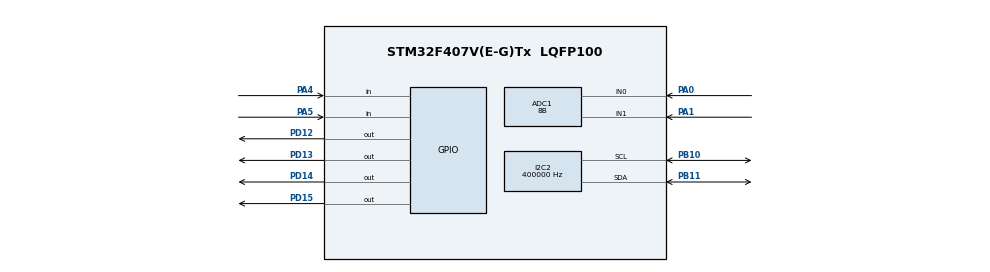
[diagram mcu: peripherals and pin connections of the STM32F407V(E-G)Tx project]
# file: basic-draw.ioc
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ADC1.Channel-2\#ChannelRegularConversion=ADC_CHANNEL_0
ADC1.Channel-3\#ChannelRegularConversion=ADC_CHANNEL_1
ADC1.ClockPrescaler=ADC_CLOCK_SYNC_PCLK_DIV4
ADC1.ContinuousConvMode=ENABLE
ADC1.DMAContinuousRequests=ENABLE
ADC1.EOCSelection=ADC_EOC_SEQ_CONV
ADC1.NbrOfConversion=2
ADC1.NbrOfConversionFlag=1
ADC1.Rank-2\#ChannelRegularConversion=1
ADC1.Rank-3\#ChannelRegularConversion=2
ADC1.Resolution=ADC_RESOLUTION_8B
ADC1.SamplingTime-2\#ChannelRegularConversion=ADC_SAMPLETIME_480CYCLES
ADC1.SamplingTime-3\#ChannelRegularConversion=ADC_SAMPLETIME_480CYCLES
ADC1.ScanConvMode=ENABLE
ADC1.master=1
Dma.ADC1.0.Direction=DMA_PERIPH_TO_MEMORY
Dma.ADC1.0.FIFOMode=DMA_FIFOMODE_DISABLE
Dma.ADC1.0.Instance=DMA2_Stream0
Dma.ADC1.0.MemDataAlignment=DMA_MDATAALIGN_BYTE
Dma.ADC1.0.MemInc=DMA_MINC_ENABLE
Dma.ADC1.0.Mode=DMA_CIRCULAR
Dma.ADC1.0.PeriphDataAlignment=DMA_PDATAALIGN_BYTE
Dma.ADC1.0.PeriphInc=DMA_PINC_DISABLE
Dma.ADC1.0.Priority=DMA_PRIORITY_LOW
Dma.Request0=ADC1
I2C2.ClockSpeed=400000
I2C2.DutyCycle=I2C_DUTYCYCLE_16_9
I2C2.I2C_Mode=I2C_Fast
Mcu.Family=STM32F4
Mcu.Name=STM32F407V(E-G)Tx
Mcu.Package=LQFP100
NVIC.DMA2_Stream0_IRQn=true\:0\:0\:false\:false\:true\:false\:true
NVIC.PriorityGroup=NVIC_PRIORITYGROUP_4
NVIC.TIM2_IRQn=true\:0\:0\:false\:false\:true\:true\:true
PA0-WKUP.Signal=SharedAnalog_PA0
PA1.Signal=SharedAnalog_PA1
PA4.GPIO_PuPd=GPIO_PULLDOWN
PA4.Signal=GPIO_Input
PA5.GPIO_PuPd=GPIO_PULLDOWN
PA5.Signal=GPIO_Input
PB10.Mode=I2C
PB10.Signal=I2C2_SCL
PB11.Mode=I2C
PB11.Signal=I2C2_SDA
PD12.Signal=GPIO_Output
PD13.GPIO_Speed=GPIO_SPEED_FREQ_VERY_HIGH
PD13.Signal=GPIO_Output
PD14.Signal=GPIO_Output
PD15.Signal=GPIO_Output
ProjectManager.HeapSize=0x200
ProjectManager.StackSize=0x400
ProjectManager.TargetToolchain=STM32CubeIDE
RCC.48MHZClocksFreq_Value=84000000
RCC.AHBFreq_Value=168000000
RCC.APB1CLKDivider=RCC_HCLK_DIV16
RCC.APB1Freq_Value=10500000
RCC.APB1TimFreq_Value=21000000
RCC.APB2Freq_Value=168000000
RCC.APB2TimFreq_Value=168000000
RCC.CortexFreq_Value=168000000
RCC.HCLKFreq_Value=168000000
RCC.HSE_VALUE=25000000
RCC.HSI_VALUE=16000000
RCC.LSE_VALUE=32768
RCC.PLLM=8
RCC.PLLN=168
RCC.SYSCLKFreq_VALUE=168000000
RCC.SYSCLKSource=RCC_SYSCLKSOURCE_PLLCLK
RCC.VCOOutputFreq_Value=336000000
SH.SharedAnalog_PA0.0=GPIO_Analog
SH.SharedAnalog_PA0.1=ADC2_IN0
SH.SharedAnalog_PA0.2=ADC1_IN0,IN0
SH.SharedAnalog_PA1.0=GPIO_Analog
SH.SharedAnalog_PA1.1=ADC1_IN1,IN1
TIM2.CounterMode=TIM_COUNTERMODE_UP
TIM2.Period=50
TIM2.Prescaler=21000-1
TIM2.TIM_MasterOutputTrigger=TIM_TRGO_UPDATE
VP_TIM2_VS_ClockSourceINT.Mode=Internal
board=custom

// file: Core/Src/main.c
/* USER CODE BEGIN Header */
/**
  ******************************************************************************
  * @file           : main.c
  * @brief          : Main program body
  ******************************************************************************
  * @attention
  *
  * Copyright (c) 2022 STMicroelectronics.
  * All rights reserved.
  *
  * This software is licensed under terms that can be found in the LICENSE file
  * in the root directory of this software component.
  * If no LICENSE file comes with this software, it is provided AS-IS.
  *
  ******************************************************************************
  */
/* USER CODE END Header */
#include "main.h"

/* USER CODE BEGIN Includes */
#include <stdio.h>
#include "user_main.h"
/* USER CODE END Includes */

ADC_HandleTypeDef hadc1;
DMA_HandleTypeDef hdma_adc1;

I2C_HandleTypeDef hi2c2;

TIM_HandleTypeDef htim2;

void SystemClock_Config(void);
static void MX_TIM2_Init(void);
static void MX_GPIO_Init(void);
static void MX_I2C2_Init(void);
static void MX_DMA_Init(void);
static void MX_ADC1_Init(void);

int main(void)
{

  /* MCU Configuration--------------------------------------------------------*/

  /* Reset of all peripherals, Initializes the Flash interface and the Systick. */
  HAL_Init();

  /* Configure the system clock */
  SystemClock_Config();

  /* Initialize all configured peripherals */
  MX_TIM2_Init();
  MX_GPIO_Init();
  MX_I2C2_Init();
  MX_DMA_Init();
  MX_ADC1_Init();
  /* USER CODE BEGIN 2 */
  user_main();
  /* USER CODE END 2 */

  /* Infinite loop */
  while (1)
  {

  }
}

void SystemClock_Config(void)
{
  RCC_OscInitTypeDef RCC_OscInitStruct = {0};
  RCC_ClkInitTypeDef RCC_ClkInitStruct = {0};

  /** Configure the main internal regulator output voltage
  */
  __HAL_RCC_PWR_CLK_ENABLE();
  __HAL_PWR_VOLTAGESCALING_CONFIG(PWR_REGULATOR_VOLTAGE_SCALE1);
  /** Initializes the RCC Oscillators according to the specified parameters
  * in the RCC_OscInitTypeDef structure.
  */
  RCC_OscInitStruct.OscillatorType = RCC_OSCILLATORTYPE_HSI;
  RCC_OscInitStruct.HSIState = RCC_HSI_ON;
  RCC_OscInitStruct.HSICalibrationValue = RCC_HSICALIBRATION_DEFAULT;
  RCC_OscInitStruct.PLL.PLLState = RCC_PLL_ON;
  RCC_OscInitStruct.PLL.PLLSource = RCC_PLLSOURCE_HSI;
  RCC_OscInitStruct.PLL.PLLM = 8;
  RCC_OscInitStruct.PLL.PLLN = 168;
  RCC_OscInitStruct.PLL.PLLP = RCC_PLLP_DIV2;
  RCC_OscInitStruct.PLL.PLLQ = 4;
  if (HAL_RCC_OscConfig(&RCC_OscInitStruct) != HAL_OK)
  {
    Error_Handler();
  }
  /** Initializes the CPU, AHB and APB buses clocks
  */
  RCC_ClkInitStruct.ClockType = RCC_CLOCKTYPE_HCLK|RCC_CLOCKTYPE_SYSCLK
                              |RCC_CLOCKTYPE_PCLK1|RCC_CLOCKTYPE_PCLK2;
  RCC_ClkInitStruct.SYSCLKSource = RCC_SYSCLKSOURCE_PLLCLK;
  RCC_ClkInitStruct.AHBCLKDivider = RCC_SYSCLK_DIV1;
  RCC_ClkInitStruct.APB1CLKDivider = RCC_HCLK_DIV16;
  RCC_ClkInitStruct.APB2CLKDivider = RCC_HCLK_DIV2;

  if (HAL_RCC_ClockConfig(&RCC_ClkInitStruct, FLASH_LATENCY_5) != HAL_OK)
  {
    Error_Handler();
  }
}

static void MX_ADC1_Init(void)
{

  ADC_ChannelConfTypeDef sConfig = {0};

  /** Configure the global features of the ADC (Clock, Resolution, Data Alignment and number of conversion)
  */
  hadc1.Instance = ADC1;
  hadc1.Init.ClockPrescaler = ADC_CLOCK_SYNC_PCLK_DIV4;
  hadc1.Init.Resolution = ADC_RESOLUTION_8B;
  hadc1.Init.ScanConvMode = ENABLE;
  hadc1.Init.ContinuousConvMode = ENABLE;
  hadc1.Init.DiscontinuousConvMode = DISABLE;
  hadc1.Init.ExternalTrigConvEdge = ADC_EXTERNALTRIGCONVEDGE_NONE;
  hadc1.Init.ExternalTrigConv = ADC_SOFTWARE_START;
  hadc1.Init.DataAlign = ADC_DATAALIGN_RIGHT;
  hadc1.Init.NbrOfConversion = 2;
  hadc1.Init.DMAContinuousRequests = ENABLE;
  hadc1.Init.EOCSelection = ADC_EOC_SEQ_CONV;
  if (HAL_ADC_Init(&hadc1) != HAL_OK)
  {
    Error_Handler();
  }
  /** Configure for the selected ADC regular channel its corresponding rank in the sequencer and its sample time.
  */
  sConfig.Channel = ADC_CHANNEL_0;
  sConfig.Rank = 1;
  sConfig.SamplingTime = ADC_SAMPLETIME_480CYCLES;
  if (HAL_ADC_ConfigChannel(&hadc1, &sConfig) != HAL_OK)
  {
    Error_Handler();
  }
  /** Configure for the selected ADC regular channel its corresponding rank in the sequencer and its sample time.
  */
  sConfig.Channel = ADC_CHANNEL_1;
  sConfig.Rank = 2;
  if (HAL_ADC_ConfigChannel(&hadc1, &sConfig) != HAL_OK)
  {
    Error_Handler();
  }

}

static void MX_I2C2_Init(void)
{

  hi2c2.Instance = I2C2;
  hi2c2.Init.ClockSpeed = 400000;
  hi2c2.Init.DutyCycle = I2C_DUTYCYCLE_16_9;
  hi2c2.Init.OwnAddress1 = 0;
  hi2c2.Init.AddressingMode = I2C_ADDRESSINGMODE_7BIT;
  hi2c2.Init.DualAddressMode = I2C_DUALADDRESS_DISABLE;
  hi2c2.Init.OwnAddress2 = 0;
  hi2c2.Init.GeneralCallMode = I2C_GENERALCALL_DISABLE;
  hi2c2.Init.NoStretchMode = I2C_NOSTRETCH_DISABLE;
  if (HAL_I2C_Init(&hi2c2) != HAL_OK)
  {
    Error_Handler();
  }

}

static void MX_TIM2_Init(void)
{

  TIM_ClockConfigTypeDef sClockSourceConfig = {0};
  TIM_MasterConfigTypeDef sMasterConfig = {0};

  htim2.Instance = TIM2;
  htim2.Init.Prescaler = 21000-1;
  htim2.Init.CounterMode = TIM_COUNTERMODE_UP;
  htim2.Init.Period = 50;
  htim2.Init.ClockDivision = TIM_CLOCKDIVISION_DIV1;
  htim2.Init.AutoReloadPreload = TIM_AUTORELOAD_PRELOAD_DISABLE;
  if (HAL_TIM_Base_Init(&htim2) != HAL_OK)
  {
    Error_Handler();
  }
  sClockSourceConfig.ClockSource = TIM_CLOCKSOURCE_INTERNAL;
  if (HAL_TIM_ConfigClockSource(&htim2, &sClockSourceConfig) != HAL_OK)
  {
    Error_Handler();
  }
  sMasterConfig.MasterOutputTrigger = TIM_TRGO_UPDATE;
  sMasterConfig.MasterSlaveMode = TIM_MASTERSLAVEMODE_DISABLE;
  if (HAL_TIMEx_MasterConfigSynchronization(&htim2, &sMasterConfig) != HAL_OK)
  {
    Error_Handler();
  }

}

static void MX_DMA_Init(void)
{

  /* DMA controller clock enable */
  __HAL_RCC_DMA2_CLK_ENABLE();

  /* DMA interrupt init */
  /* DMA2_Stream0_IRQn interrupt configuration */
  HAL_NVIC_SetPriority(DMA2_Stream0_IRQn, 0, 0);
  HAL_NVIC_EnableIRQ(DMA2_Stream0_IRQn);

}

static void MX_GPIO_Init(void)
{
  GPIO_InitTypeDef GPIO_InitStruct = {0};

  /* GPIO Ports Clock Enable */
  __HAL_RCC_GPIOA_CLK_ENABLE();
  __HAL_RCC_GPIOB_CLK_ENABLE();
  __HAL_RCC_GPIOD_CLK_ENABLE();

  /*Configure GPIO pin Output Level */
  HAL_GPIO_WritePin(GPIOD, GPIO_PIN_12|GPIO_PIN_13|GPIO_PIN_14|GPIO_PIN_15, GPIO_PIN_RESET);

  /*Configure GPIO pin : PA0 */
  GPIO_InitStruct.Pin = GPIO_PIN_0;
  GPIO_InitStruct.Mode = GPIO_MODE_ANALOG;
  GPIO_InitStruct.Pull = GPIO_NOPULL;
  HAL_GPIO_Init(GPIOA, &GPIO_InitStruct);

  /*Configure GPIO pins : PA4 PA5 */
  GPIO_InitStruct.Pin = GPIO_PIN_4|GPIO_PIN_5;
  GPIO_InitStruct.Mode = GPIO_MODE_INPUT;
  GPIO_InitStruct.Pull = GPIO_PULLDOWN;
  HAL_GPIO_Init(GPIOA, &GPIO_InitStruct);

  /*Configure GPIO pins : PD12 PD14 PD15 */
  GPIO_InitStruct.Pin = GPIO_PIN_12|GPIO_PIN_14|GPIO_PIN_15;
  GPIO_InitStruct.Mode = GPIO_MODE_OUTPUT_PP;
  GPIO_InitStruct.Pull = GPIO_NOPULL;
  GPIO_InitStruct.Speed = GPIO_SPEED_FREQ_LOW;
  HAL_GPIO_Init(GPIOD, &GPIO_InitStruct);

  /*Configure GPIO pin : PD13 */
  GPIO_InitStruct.Pin = GPIO_PIN_13;
  GPIO_InitStruct.Mode = GPIO_MODE_OUTPUT_PP;
  GPIO_InitStruct.Pull = GPIO_NOPULL;
  GPIO_InitStruct.Speed = GPIO_SPEED_FREQ_VERY_HIGH;
  HAL_GPIO_Init(GPIOD, &GPIO_InitStruct);

}

/* USER CODE BEGIN 4 */
int _write(int file, char *ptr, int len)
{
  for (int index = 0; index < len; index++) {
    ITM_SendChar(*ptr++);
  }
  return len;
}
/* USER CODE END 4 */

void Error_Handler(void)
{
  __disable_irq();
  while (1)
  {
  }
}

/************************ (C) COPYRIGHT STMicroelectronics *****END OF FILE****/
